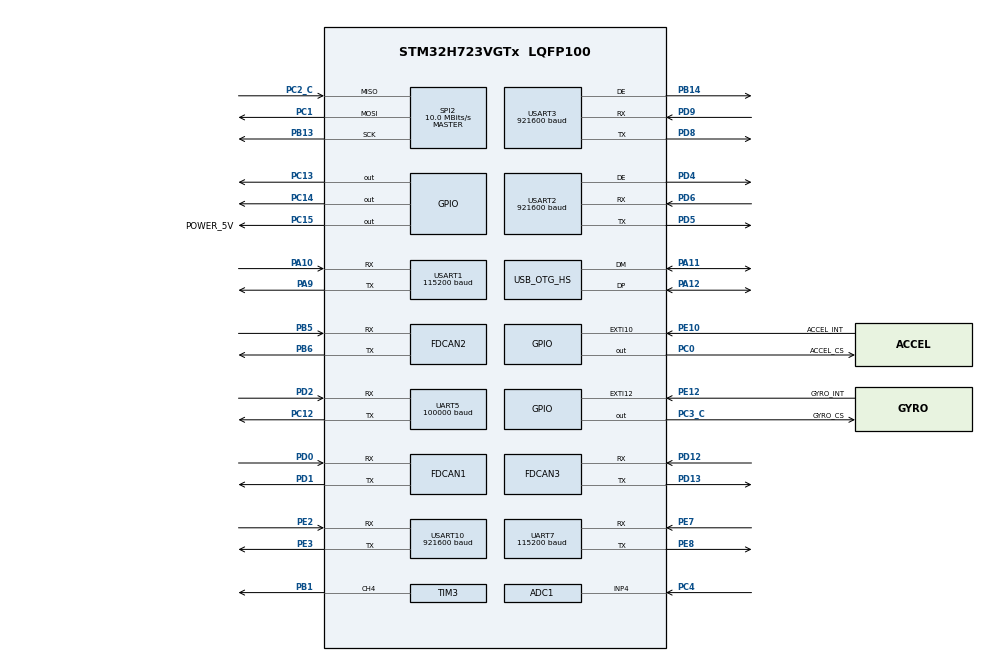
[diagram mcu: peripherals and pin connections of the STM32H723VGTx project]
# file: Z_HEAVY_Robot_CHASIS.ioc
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ADC1.Channel-2\#ChannelRegularConversion=ADC_CHANNEL_4
ADC1.Channel-3\#ChannelRegularConversion=ADC_CHANNEL_4
ADC1.ClockPrescaler=ADC_CLOCK_ASYNC_DIV64
ADC1.ClockPrescalerADC3=ADC_CLOCK_SYNC_PCLK_DIV4
ADC1.ContinuousConvMode=ENABLE
ADC1.ConversionDataManagement=ADC_CONVERSIONDATA_DMA_CIRCULAR
ADC1.NbrOfConversion=2
ADC1.NbrOfConversionFlag=1
ADC1.OffsetNumber-2\#ChannelRegularConversion=ADC_OFFSET_NONE
ADC1.OffsetNumber-3\#ChannelRegularConversion=ADC_OFFSET_NONE
ADC1.OffsetSignedSaturation-2\#ChannelRegularConversion=DISABLE
ADC1.OffsetSignedSaturation-3\#ChannelRegularConversion=DISABLE
ADC1.Rank-2\#ChannelRegularConversion=1
ADC1.Rank-3\#ChannelRegularConversion=2
ADC1.SamplingTime-2\#ChannelRegularConversion=ADC_SAMPLETIME_32CYCLES_5
ADC1.SamplingTime-3\#ChannelRegularConversion=ADC_SAMPLETIME_1CYCLE_5
ADC1.master=1
ADC3.Channel-0\#ChannelRegularConversion=ADC_CHANNEL_TEMPSENSOR
ADC3.ClockPrescalerADC3=ADC_CLOCK_SYNC_PCLK_DIV4
ADC3.DiscontinuousConvMode=ENABLE
ADC3.NbrOfConversionFlag=1
ADC3.OffsetNumber-0\#ChannelRegularConversion=ADC_OFFSET_NONE
ADC3.OffsetSign-0\#ChannelRegularConversion=ADC3_OFFSET_SIGN_NEGATIVE
ADC3.Rank-0\#ChannelRegularConversion=1
ADC3.SamplingTime-0\#ChannelRegularConversion=ADC3_SAMPLETIME_2CYCLES_5
Bdma.ADC3.0.Direction=DMA_PERIPH_TO_MEMORY
Bdma.ADC3.0.EventEnable=DISABLE
Bdma.ADC3.0.Instance=BDMA_Channel0
Bdma.ADC3.0.MemDataAlignment=DMA_MDATAALIGN_HALFWORD
Bdma.ADC3.0.MemInc=DMA_MINC_ENABLE
Bdma.ADC3.0.Mode=DMA_CIRCULAR
Bdma.ADC3.0.PeriphDataAlignment=DMA_PDATAALIGN_HALFWORD
Bdma.ADC3.0.PeriphInc=DMA_PINC_DISABLE
Bdma.ADC3.0.Polarity=HAL_DMAMUX_REQ_GEN_RISING
Bdma.ADC3.0.Priority=DMA_PRIORITY_LOW
Bdma.ADC3.0.RequestNumber=1
Bdma.ADC3.0.SignalID=NONE
Bdma.ADC3.0.SyncEnable=DISABLE
Bdma.ADC3.0.SyncPolarity=HAL_DMAMUX_SYNC_NO_EVENT
Bdma.ADC3.0.SyncRequestNumber=1
Bdma.ADC3.0.SyncSignalID=NONE
Bdma.Request0=ADC3
Bdma.RequestsNb=1
CORTEX_M7.AccessPermission-Cortex_Memory_Protection_Unit_Region0_Settings=MPU_REGION_FULL_ACCESS
CORTEX_M7.AccessPermission_Spec=MPU_REGION_FULL_ACCESS
CORTEX_M7.BaseAddress-Cortex_Memory_Protection_Unit_Region0_Settings=0x24000000
CORTEX_M7.BaseAddress_Spec=0x24000000
CORTEX_M7.CPU_DCache=Enabled
CORTEX_M7.CPU_ICache=Enabled
CORTEX_M7.DisableExec_Spec=MPU_INSTRUCTION_ACCESS_ENABLE
CORTEX_M7.Enable-Cortex_Memory_Protection_Unit_Region0_Settings=MPU_REGION_ENABLE
CORTEX_M7.IsBufferable_Spec=MPU_ACCESS_NOT_BUFFERABLE
CORTEX_M7.IsCacheable_Spec=MPU_ACCESS_NOT_CACHEABLE
CORTEX_M7.IsShareable_Spec=MPU_ACCESS_NOT_SHAREABLE
CORTEX_M7.MPU_Control=MPU_HFNMI_PRIVDEF
CORTEX_M7.Size-Cortex_Memory_Protection_Unit_Region0_Settings=MPU_REGION_SIZE_512KB
CORTEX_M7.Size_Spec=MPU_REGION_SIZE_512KB
CORTEX_M7.SubRegionDisable_Spec=0x0
CORTEX_M7.TypeExtField-Cortex_Memory_Protection_Unit_Region0_Settings=MPU_TEX_LEVEL1
CORTEX_M7.TypeExtField_Spec=MPU_TEX_LEVEL1
CORTEX_M7.default_mode_Activation=1
Dma.ADC1.14.Direction=DMA_PERIPH_TO_MEMORY
Dma.ADC1.14.EventEnable=DISABLE
Dma.ADC1.14.FIFOMode=DMA_FIFOMODE_DISABLE
Dma.ADC1.14.Instance=DMA2_Stream6
Dma.ADC1.14.MemDataAlignment=DMA_MDATAALIGN_HALFWORD
Dma.ADC1.14.MemInc=DMA_MINC_ENABLE
Dma.ADC1.14.Mode=DMA_CIRCULAR
Dma.ADC1.14.PeriphDataAlignment=DMA_PDATAALIGN_HALFWORD
Dma.ADC1.14.PeriphInc=DMA_PINC_DISABLE
Dma.ADC1.14.Polarity=HAL_DMAMUX_REQ_GEN_RISING
Dma.ADC1.14.Priority=DMA_PRIORITY_LOW
Dma.ADC1.14.RequestNumber=1
Dma.ADC1.14.SignalID=NONE
Dma.ADC1.14.SyncEnable=DISABLE
Dma.ADC1.14.SyncPolarity=HAL_DMAMUX_SYNC_NO_EVENT
Dma.ADC1.14.SyncRequestNumber=1
Dma.ADC1.14.SyncSignalID=NONE
Dma.MEMTOMEM.11.Direction=DMA_MEMORY_TO_MEMORY
Dma.MEMTOMEM.11.EventEnable=DISABLE
Dma.MEMTOMEM.11.FIFOMode=DMA_FIFOMODE_ENABLE
Dma.MEMTOMEM.11.FIFOThreshold=DMA_FIFO_THRESHOLD_FULL
Dma.MEMTOMEM.11.Instance=DMA1_Stream0
Dma.MEMTOMEM.11.MemBurst=DMA_MBURST_SINGLE
Dma.MEMTOMEM.11.MemDataAlignment=DMA_MDATAALIGN_BYTE
Dma.MEMTOMEM.11.MemInc=DMA_MINC_ENABLE
Dma.MEMTOMEM.11.Mode=DMA_NORMAL
Dma.MEMTOMEM.11.PeriphBurst=DMA_PBURST_SINGLE
Dma.MEMTOMEM.11.PeriphDataAlignment=DMA_PDATAALIGN_BYTE
Dma.MEMTOMEM.11.PeriphInc=DMA_PINC_ENABLE
Dma.MEMTOMEM.11.Polarity=HAL_DMAMUX_REQ_GEN_RISING
Dma.MEMTOMEM.11.Priority=DMA_PRIORITY_LOW
Dma.MEMTOMEM.11.RequestNumber=1
Dma.MEMTOMEM.11.SignalID=NONE
Dma.MEMTOMEM.11.SyncEnable=DISABLE
Dma.MEMTOMEM.11.SyncPolarity=HAL_DMAMUX_SYNC_NO_EVENT
Dma.MEMTOMEM.11.SyncRequestNumber=1
Dma.MEMTOMEM.11.SyncSignalID=NONE
Dma.Request0=UART5_RX
Dma.Request1=SPI2_RX
Dma.Request10=USART3_TX
Dma.Request11=MEMTOMEM
Dma.Request12=USART10_RX
Dma.Request13=USART10_TX
Dma.Request14=ADC1
Dma.Request2=SPI2_TX
Dma.Request3=UART7_RX
Dma.Request4=UART7_TX
Dma.Request5=USART1_RX
Dma.Request6=USART1_TX
Dma.Request7=USART2_RX
Dma.Request8=USART2_TX
Dma.Request9=USART3_RX
Dma.SPI2_RX.1.Direction=DMA_PERIPH_TO_MEMORY
Dma.SPI2_RX.1.EventEnable=DISABLE
Dma.SPI2_RX.1.FIFOMode=DMA_FIFOMODE_DISABLE
Dma.SPI2_RX.1.Instance=DMA1_Stream1
Dma.SPI2_RX.1.MemDataAlignment=DMA_MDATAALIGN_BYTE
Dma.SPI2_RX.1.MemInc=DMA_MINC_ENABLE
Dma.SPI2_RX.1.Mode=DMA_NORMAL
Dma.SPI2_RX.1.PeriphDataAlignment=DMA_PDATAALIGN_BYTE
Dma.SPI2_RX.1.PeriphInc=DMA_PINC_DISABLE
Dma.SPI2_RX.1.Polarity=HAL_DMAMUX_REQ_GEN_RISING
Dma.SPI2_RX.1.Priority=DMA_PRIORITY_VERY_HIGH
Dma.SPI2_RX.1.RequestNumber=1
Dma.SPI2_RX.1.SignalID=NONE
Dma.SPI2_RX.1.SyncEnable=DISABLE
Dma.SPI2_RX.1.SyncPolarity=HAL_DMAMUX_SYNC_NO_EVENT
Dma.SPI2_RX.1.SyncRequestNumber=1
Dma.SPI2_RX.1.SyncSignalID=NONE
Dma.SPI2_TX.2.Direction=DMA_MEMORY_TO_PERIPH
Dma.SPI2_TX.2.EventEnable=DISABLE
Dma.SPI2_TX.2.FIFOMode=DMA_FIFOMODE_DISABLE
Dma.SPI2_TX.2.Instance=DMA1_Stream2
Dma.SPI2_TX.2.MemDataAlignment=DMA_MDATAALIGN_BYTE
Dma.SPI2_TX.2.MemInc=DMA_MINC_ENABLE
Dma.SPI2_TX.2.Mode=DMA_NORMAL
Dma.SPI2_TX.2.PeriphDataAlignment=DMA_PDATAALIGN_BYTE
Dma.SPI2_TX.2.PeriphInc=DMA_PINC_DISABLE
Dma.SPI2_TX.2.Polarity=HAL_DMAMUX_REQ_GEN_RISING
Dma.SPI2_TX.2.Priority=DMA_PRIORITY_MEDIUM
Dma.SPI2_TX.2.RequestNumber=1
Dma.SPI2_TX.2.SignalID=NONE
Dma.SPI2_TX.2.SyncEnable=DISABLE
Dma.SPI2_TX.2.SyncPolarity=HAL_DMAMUX_SYNC_NO_EVENT
Dma.SPI2_TX.2.SyncRequestNumber=1
Dma.SPI2_TX.2.SyncSignalID=NONE
Dma.UART5_RX.0.Direction=DMA_PERIPH_TO_MEMORY
Dma.UART5_RX.0.EventEnable=DISABLE
Dma.UART5_RX.0.FIFOMode=DMA_FIFOMODE_DISABLE
Dma.UART5_RX.0.Instance=DMA2_Stream3
Dma.UART5_RX.0.MemDataAlignment=DMA_MDATAALIGN_BYTE
Dma.UART5_RX.0.MemInc=DMA_MINC_ENABLE
Dma.UART5_RX.0.Mode=DMA_CIRCULAR
Dma.UART5_RX.0.PeriphDataAlignment=DMA_PDATAALIGN_BYTE
Dma.UART5_RX.0.PeriphInc=DMA_PINC_DISABLE
Dma.UART5_RX.0.Polarity=HAL_DMAMUX_REQ_GEN_RISING
Dma.UART5_RX.0.Priority=DMA_PRIORITY_VERY_HIGH
Dma.UART5_RX.0.RequestNumber=1
Dma.UART5_RX.0.SignalID=NONE
Dma.UART5_RX.0.SyncEnable=DISABLE
Dma.UART5_RX.0.SyncPolarity=HAL_DMAMUX_SYNC_NO_EVENT
Dma.UART5_RX.0.SyncRequestNumber=1
Dma.UART5_RX.0.SyncSignalID=NONE
Dma.UART7_RX.3.Direction=DMA_PERIPH_TO_MEMORY
Dma.UART7_RX.3.EventEnable=DISABLE
Dma.UART7_RX.3.FIFOMode=DMA_FIFOMODE_DISABLE
Dma.UART7_RX.3.Instance=DMA1_Stream3
Dma.UART7_RX.3.MemDataAlignment=DMA_MDATAALIGN_BYTE
Dma.UART7_RX.3.MemInc=DMA_MINC_ENABLE
Dma.UART7_RX.3.Mode=DMA_CIRCULAR
Dma.UART7_RX.3.PeriphDataAlignment=DMA_PDATAALIGN_BYTE
Dma.UART7_RX.3.PeriphInc=DMA_PINC_DISABLE
Dma.UART7_RX.3.Polarity=HAL_DMAMUX_REQ_GEN_RISING
Dma.UART7_RX.3.Priority=DMA_PRIORITY_LOW
Dma.UART7_RX.3.RequestNumber=1
Dma.UART7_RX.3.SignalID=NONE
Dma.UART7_RX.3.SyncEnable=DISABLE
Dma.UART7_RX.3.SyncPolarity=HAL_DMAMUX_SYNC_NO_EVENT
Dma.UART7_RX.3.SyncRequestNumber=1
Dma.UART7_RX.3.SyncSignalID=NONE
Dma.UART7_TX.4.Direction=DMA_MEMORY_TO_PERIPH
Dma.UART7_TX.4.EventEnable=DISABLE
Dma.UART7_TX.4.FIFOMode=DMA_FIFOMODE_DISABLE
Dma.UART7_TX.4.Instance=DMA1_Stream4
Dma.UART7_TX.4.MemDataAlignment=DMA_MDATAALIGN_BYTE
Dma.UART7_TX.4.MemInc=DMA_MINC_ENABLE
Dma.UART7_TX.4.Mode=DMA_NORMAL
Dma.UART7_TX.4.PeriphDataAlignment=DMA_PDATAALIGN_BYTE
Dma.UART7_TX.4.PeriphInc=DMA_PINC_DISABLE
Dma.UART7_TX.4.Polarity=HAL_DMAMUX_REQ_GEN_RISING
Dma.UART7_TX.4.Priority=DMA_PRIORITY_LOW
Dma.UART7_TX.4.RequestNumber=1
Dma.UART7_TX.4.SignalID=NONE
Dma.UART7_TX.4.SyncEnable=DISABLE
Dma.UART7_TX.4.SyncPolarity=HAL_DMAMUX_SYNC_NO_EVENT
Dma.UART7_TX.4.SyncRequestNumber=1
Dma.UART7_TX.4.SyncSignalID=NONE
Dma.USART10_RX.12.Direction=DMA_PERIPH_TO_MEMORY
Dma.USART10_RX.12.EventEnable=DISABLE
Dma.USART10_RX.12.FIFOMode=DMA_FIFOMODE_DISABLE
Dma.USART10_RX.12.Instance=DMA2_Stream4
Dma.USART10_RX.12.MemDataAlignment=DMA_MDATAALIGN_BYTE
Dma.USART10_RX.12.MemInc=DMA_MINC_ENABLE
Dma.USART10_RX.12.Mode=DMA_CIRCULAR
Dma.USART10_RX.12.PeriphDataAlignment=DMA_PDATAALIGN_BYTE
Dma.USART10_RX.12.PeriphInc=DMA_PINC_DISABLE
Dma.USART10_RX.12.Polarity=HAL_DMAMUX_REQ_GEN_RISING
Dma.USART10_RX.12.Priority=DMA_PRIORITY_VERY_HIGH
Dma.USART10_RX.12.RequestNumber=1
Dma.USART10_RX.12.SignalID=NONE
Dma.USART10_RX.12.SyncEnable=DISABLE
Dma.USART10_RX.12.SyncPolarity=HAL_DMAMUX_SYNC_NO_EVENT
Dma.USART10_RX.12.SyncRequestNumber=1
Dma.USART10_RX.12.SyncSignalID=NONE
Dma.USART10_TX.13.Direction=DMA_MEMORY_TO_PERIPH
Dma.USART10_TX.13.EventEnable=DISABLE
Dma.USART10_TX.13.FIFOMode=DMA_FIFOMODE_DISABLE
Dma.USART10_TX.13.Instance=DMA2_Stream5
Dma.USART10_TX.13.MemDataAlignment=DMA_MDATAALIGN_BYTE
Dma.USART10_TX.13.MemInc=DMA_MINC_ENABLE
Dma.USART10_TX.13.Mode=DMA_NORMAL
Dma.USART10_TX.13.PeriphDataAlignment=DMA_PDATAALIGN_BYTE
Dma.USART10_TX.13.PeriphInc=DMA_PINC_DISABLE
Dma.USART10_TX.13.Polarity=HAL_DMAMUX_REQ_GEN_RISING
Dma.USART10_TX.13.Priority=DMA_PRIORITY_VERY_HIGH
Dma.USART10_TX.13.RequestNumber=1
Dma.USART10_TX.13.SignalID=NONE
Dma.USART10_TX.13.SyncEnable=DISABLE
Dma.USART10_TX.13.SyncPolarity=HAL_DMAMUX_SYNC_NO_EVENT
Dma.USART10_TX.13.SyncRequestNumber=1
Dma.USART10_TX.13.SyncSignalID=NONE
Dma.USART1_RX.5.Direction=DMA_PERIPH_TO_MEMORY
Dma.USART1_RX.5.EventEnable=DISABLE
Dma.USART1_RX.5.FIFOMode=DMA_FIFOMODE_DISABLE
Dma.USART1_RX.5.Instance=DMA1_Stream5
Dma.USART1_RX.5.MemDataAlignment=DMA_MDATAALIGN_BYTE
Dma.USART1_RX.5.MemInc=DMA_MINC_ENABLE
Dma.USART1_RX.5.Mode=DMA_NORMAL
Dma.USART1_RX.5.PeriphDataAlignment=DMA_PDATAALIGN_BYTE
Dma.USART1_RX.5.PeriphInc=DMA_PINC_DISABLE
Dma.USART1_RX.5.Polarity=HAL_DMAMUX_REQ_GEN_RISING
Dma.USART1_RX.5.Priority=DMA_PRIORITY_VERY_HIGH
Dma.USART1_RX.5.RequestNumber=1
Dma.USART1_RX.5.SignalID=NONE
Dma.USART1_RX.5.SyncEnable=DISABLE
Dma.USART1_RX.5.SyncPolarity=HAL_DMAMUX_SYNC_NO_EVENT
Dma.USART1_RX.5.SyncRequestNumber=1
Dma.USART1_RX.5.SyncSignalID=NONE
Dma.USART1_TX.6.Direction=DMA_MEMORY_TO_PERIPH
Dma.USART1_TX.6.EventEnable=DISABLE
Dma.USART1_TX.6.FIFOMode=DMA_FIFOMODE_DISABLE
Dma.USART1_TX.6.Instance=DMA1_Stream6
Dma.USART1_TX.6.MemDataAlignment=DMA_MDATAALIGN_BYTE
Dma.USART1_TX.6.MemInc=DMA_MINC_ENABLE
Dma.USART1_TX.6.Mode=DMA_NORMAL
Dma.USART1_TX.6.PeriphDataAlignment=DMA_PDATAALIGN_BYTE
Dma.USART1_TX.6.PeriphInc=DMA_PINC_DISABLE
Dma.USART1_TX.6.Polarity=HAL_DMAMUX_REQ_GEN_RISING
Dma.USART1_TX.6.Priority=DMA_PRIORITY_VERY_HIGH
Dma.USART1_TX.6.RequestNumber=1
Dma.USART1_TX.6.SignalID=NONE
Dma.USART1_TX.6.SyncEnable=DISABLE
Dma.USART1_TX.6.SyncPolarity=HAL_DMAMUX_SYNC_NO_EVENT
Dma.USART1_TX.6.SyncRequestNumber=1
Dma.USART1_TX.6.SyncSignalID=NONE
Dma.USART2_RX.7.Direction=DMA_PERIPH_TO_MEMORY
Dma.USART2_RX.7.EventEnable=DISABLE
Dma.USART2_RX.7.FIFOMode=DMA_FIFOMODE_DISABLE
Dma.USART2_RX.7.Instance=DMA1_Stream7
Dma.USART2_RX.7.MemDataAlignment=DMA_MDATAALIGN_BYTE
Dma.USART2_RX.7.MemInc=DMA_MINC_ENABLE
Dma.USART2_RX.7.Mode=DMA_CIRCULAR
Dma.USART2_RX.7.PeriphDataAlignment=DMA_PDATAALIGN_BYTE
Dma.USART2_RX.7.PeriphInc=DMA_PINC_DISABLE
Dma.USART2_RX.7.Polarity=HAL_DMAMUX_REQ_GEN_RISING
Dma.USART2_RX.7.Priority=DMA_PRIORITY_MEDIUM
Dma.USART2_RX.7.RequestNumber=1
Dma.USART2_RX.7.SignalID=NONE
Dma.USART2_RX.7.SyncEnable=DISABLE
Dma.USART2_RX.7.SyncPolarity=HAL_DMAMUX_SYNC_NO_EVENT
Dma.USART2_RX.7.SyncRequestNumber=1
Dma.USART2_RX.7.SyncSignalID=NONE
Dma.USART2_TX.8.Direction=DMA_MEMORY_TO_PERIPH
Dma.USART2_TX.8.EventEnable=DISABLE
Dma.USART2_TX.8.FIFOMode=DMA_FIFOMODE_DISABLE
Dma.USART2_TX.8.Instance=DMA2_Stream0
Dma.USART2_TX.8.MemDataAlignment=DMA_MDATAALIGN_BYTE
Dma.USART2_TX.8.MemInc=DMA_MINC_ENABLE
Dma.USART2_TX.8.Mode=DMA_NORMAL
Dma.USART2_TX.8.PeriphDataAlignment=DMA_PDATAALIGN_BYTE
Dma.USART2_TX.8.PeriphInc=DMA_PINC_DISABLE
Dma.USART2_TX.8.Polarity=HAL_DMAMUX_REQ_GEN_RISING
Dma.USART2_TX.8.Priority=DMA_PRIORITY_MEDIUM
Dma.USART2_TX.8.RequestNumber=1
Dma.USART2_TX.8.SignalID=NONE
Dma.USART2_TX.8.SyncEnable=DISABLE
Dma.USART2_TX.8.SyncPolarity=HAL_DMAMUX_SYNC_NO_EVENT
Dma.USART2_TX.8.SyncRequestNumber=1
Dma.USART2_TX.8.SyncSignalID=NONE
Dma.USART3_RX.9.Direction=DMA_PERIPH_TO_MEMORY
Dma.USART3_RX.9.EventEnable=DISABLE
Dma.USART3_RX.9.FIFOMode=DMA_FIFOMODE_DISABLE
Dma.USART3_RX.9.Instance=DMA2_Stream1
Dma.USART3_RX.9.MemDataAlignment=DMA_MDATAALIGN_BYTE
Dma.USART3_RX.9.MemInc=DMA_MINC_ENABLE
Dma.USART3_RX.9.Mode=DMA_CIRCULAR
Dma.USART3_RX.9.PeriphDataAlignment=DMA_PDATAALIGN_BYTE
Dma.USART3_RX.9.PeriphInc=DMA_PINC_DISABLE
Dma.USART3_RX.9.Polarity=HAL_DMAMUX_REQ_GEN_RISING
Dma.USART3_RX.9.Priority=DMA_PRIORITY_MEDIUM
Dma.USART3_RX.9.RequestNumber=1
Dma.USART3_RX.9.SignalID=NONE
Dma.USART3_RX.9.SyncEnable=DISABLE
Dma.USART3_RX.9.SyncPolarity=HAL_DMAMUX_SYNC_NO_EVENT
Dma.USART3_RX.9.SyncRequestNumber=1
Dma.USART3_RX.9.SyncSignalID=NONE
Dma.USART3_TX.10.Direction=DMA_MEMORY_TO_PERIPH
Dma.USART3_TX.10.EventEnable=DISABLE
Dma.USART3_TX.10.FIFOMode=DMA_FIFOMODE_DISABLE
Dma.USART3_TX.10.Instance=DMA2_Stream2
Dma.USART3_TX.10.MemDataAlignment=DMA_MDATAALIGN_BYTE
Dma.USART3_TX.10.MemInc=DMA_MINC_ENABLE
Dma.USART3_TX.10.Mode=DMA_NORMAL
Dma.USART3_TX.10.PeriphDataAlignment=DMA_PDATAALIGN_BYTE
Dma.USART3_TX.10.PeriphInc=DMA_PINC_DISABLE
Dma.USART3_TX.10.Polarity=HAL_DMAMUX_REQ_GEN_RISING
Dma.USART3_TX.10.Priority=DMA_PRIORITY_MEDIUM
Dma.USART3_TX.10.RequestNumber=1
Dma.USART3_TX.10.SignalID=NONE
Dma.USART3_TX.10.SyncEnable=DISABLE
Dma.USART3_TX.10.SyncPolarity=HAL_DMAMUX_SYNC_NO_EVENT
Dma.USART3_TX.10.SyncRequestNumber=1
Dma.USART3_TX.10.SyncSignalID=NONE
FDCAN1.AutoRetransmission=DISABLE
FDCAN1.CalculateBaudRateNominal=1000000
FDCAN1.CalculateTimeBitNominal=1000
FDCAN1.CalculateTimeQuantumNominal=50.0
FDCAN1.ClockCalibrationCCU=DISABLE
FDCAN1.DataPrescaler=5
FDCAN1.DataSyncJumpWidth=5
FDCAN1.DataTimeSeg1=14
FDCAN1.DataTimeSeg2=5
FDCAN1.ExtFiltersNbr=0
FDCAN1.FrameFormat=FDCAN_FRAME_CLASSIC
FDCAN1.NominalPrescaler=5
FDCAN1.NominalSyncJumpWidth=5
FDCAN1.NominalTimeSeg1=14
FDCAN1.NominalTimeSeg2=5
FDCAN1.ProtocolException=ENABLE
FDCAN1.RxBufferSize=FDCAN_DATA_BYTES_8
FDCAN1.RxFifo0ElmtSize=FDCAN_DATA_BYTES_8
FDCAN1.RxFifo0ElmtsNbr=8
FDCAN1.RxFifo1ElmtSize=FDCAN_DATA_BYTES_8
FDCAN1.StdFiltersNbr=1
FDCAN1.TransmitPause=DISABLE
FDCAN1.TxElmtSize=FDCAN_DATA_BYTES_8
FDCAN1.TxFifoQueueElmtsNbr=8
FDCAN1.TxFifoQueueMode=FDCAN_TX_FIFO_OPERATION
FDCAN2.CalculateBaudRateNominal=1000000
FDCAN2.CalculateTimeBitNominal=1000
FDCAN2.CalculateTimeQuantumNominal=50.0
FDCAN2.DataPrescaler=1
FDCAN2.DataSyncJumpWidth=5
FDCAN2.DataTimeSeg1=14
FDCAN2.DataTimeSeg2=5
FDCAN2.FrameFormat=FDCAN_FRAME_CLASSIC
FDCAN2.MessageRAMOffset=853
FDCAN2.NominalPrescaler=5
FDCAN2.NominalSyncJumpWidth=5
FDCAN2.NominalTimeSeg1=14
FDCAN2.NominalTimeSeg2=5
FDCAN2.ProtocolException=ENABLE
FDCAN2.RxFifo0ElmtsNbr=0
FDCAN2.RxFifo1ElmtsNbr=8
FDCAN2.StdFiltersNbr=1
FDCAN2.TxFifoQueueElmtsNbr=8
FDCAN3.CalculateBaudRateNominal=1000000
FDCAN3.CalculateTimeBitNominal=1000
FDCAN3.CalculateTimeQuantumNominal=50.0
FDCAN3.DataPrescaler=5
FDCAN3.DataSyncJumpWidth=5
FDCAN3.DataTimeSeg1=14
FDCAN3.DataTimeSeg2=5
FDCAN3.FrameFormat=FDCAN_FRAME_CLASSIC
FDCAN3.MessageRAMOffset=1706
FDCAN3.NominalPrescaler=5
FDCAN3.NominalSyncJumpWidth=5
FDCAN3.NominalTimeSeg1=14
FDCAN3.NominalTimeSeg2=5
FDCAN3.ProtocolException=ENABLE
FDCAN3.RxFifo0ElmtsNbr=8
FDCAN3.StdFiltersNbr=1
FDCAN3.TxFifoQueueElmtsNbr=8
FREERTOS.INCLUDE_vTaskDelayUntil=1
FREERTOS.Tasks01=Start_INS_Task,2,2048,INS_Task,As weak,NULL,Static,Start_INS_TaskBuffer,Start_INS_TaskControlBlock;Start_Control_Task,1,2048,Control_Task,As weak,NULL,Static,Start_Control_TaskBuffer,Start_Control_TaskControlBlock;Start_CAN_Task,0,2048,CAN_Task,As weak,NULL,Static,Start_CAN_TaskBuffer,Start_CAN_TaskControlBlock;Start_Detect_Task,-1,2048,Detect_Task,As weak,NULL,Static,Start_Detect_TaskBuffer,Start_Detect_TaskControlBlock
FREERTOS.configMAX_TASK_NAME_LEN=64
FREERTOS.configMINIMAL_STACK_SIZE=2048
FREERTOS.configQUEUE_REGISTRY_SIZE=8
FREERTOS.configUSE_TRACE_FACILITY=1
Mcu.Family=STM32H7
Mcu.Name=STM32H723VGTx
Mcu.Package=LQFP100
NVIC.BDMA_Channel0_IRQn=true\:5\:0\:false\:false\:true\:true\:false\:true\:true
NVIC.DMA1_Stream0_IRQn=true\:5\:0\:false\:false\:true\:true\:false\:true\:true
NVIC.DMA1_Stream1_IRQn=true\:5\:0\:false\:false\:true\:true\:false\:true\:true
NVIC.DMA1_Stream2_IRQn=true\:5\:0\:false\:false\:true\:true\:false\:true\:true
NVIC.DMA1_Stream3_IRQn=true\:5\:0\:false\:false\:true\:true\:false\:true\:true
NVIC.DMA1_Stream4_IRQn=true\:5\:0\:false\:false\:true\:true\:false\:true\:true
NVIC.DMA1_Stream5_IRQn=true\:5\:0\:false\:false\:true\:true\:false\:true\:true
NVIC.DMA1_Stream6_IRQn=true\:5\:0\:false\:false\:true\:true\:false\:true\:true
NVIC.DMA1_Stream7_IRQn=true\:5\:0\:false\:false\:true\:true\:false\:true\:true
NVIC.DMA2_Stream0_IRQn=true\:5\:0\:false\:false\:true\:true\:false\:true\:true
NVIC.DMA2_Stream1_IRQn=true\:5\:0\:false\:false\:true\:true\:false\:true\:true
NVIC.DMA2_Stream2_IRQn=true\:5\:0\:false\:false\:true\:true\:false\:true\:true
NVIC.DMA2_Stream3_IRQn=true\:5\:0\:false\:false\:true\:true\:false\:true\:true
NVIC.DMA2_Stream4_IRQn=true\:5\:0\:false\:false\:true\:true\:false\:true\:true
NVIC.DMA2_Stream5_IRQn=true\:5\:0\:false\:false\:true\:true\:false\:true\:true
NVIC.DMA2_Stream6_IRQn=true\:5\:0\:false\:false\:true\:true\:false\:true\:true
NVIC.FDCAN1_IT0_IRQn=true\:5\:0\:false\:false\:true\:true\:true\:true\:true
NVIC.FDCAN1_IT1_IRQn=true\:5\:0\:false\:false\:true\:true\:true\:true\:true
NVIC.FDCAN2_IT0_IRQn=true\:5\:0\:false\:false\:true\:true\:true\:true\:true
NVIC.FDCAN2_IT1_IRQn=true\:5\:0\:false\:false\:true\:true\:true\:true\:true
NVIC.FDCAN3_IT0_IRQn=true\:5\:0\:false\:false\:true\:true\:true\:true\:true
NVIC.FDCAN3_IT1_IRQn=true\:5\:0\:false\:false\:true\:true\:true\:true\:true
NVIC.OTG_HS_IRQn=true\:5\:0\:false\:false\:true\:true\:true\:true\:true
NVIC.PriorityGroup=NVIC_PRIORITYGROUP_4
NVIC.SPI2_IRQn=true\:5\:0\:true\:false\:true\:true\:false\:true\:true
NVIC.TIM2_IRQn=true\:15\:0\:false\:false\:true\:false\:false\:true\:true
NVIC.TimeBase=TIM2_IRQn
NVIC.TimeBaseIP=TIM2
NVIC.UART5_IRQn=true\:5\:0\:false\:false\:true\:true\:true\:true\:true
NVIC.UART7_IRQn=true\:5\:0\:false\:false\:true\:true\:true\:true\:true
NVIC.USART10_IRQn=true\:5\:0\:false\:false\:true\:true\:true\:true\:true
NVIC.USART1_IRQn=true\:5\:0\:false\:false\:true\:true\:true\:true\:true
NVIC.USART2_IRQn=true\:5\:0\:false\:false\:true\:true\:true\:true\:true
NVIC.USART3_IRQn=true\:5\:0\:false\:false\:true\:true\:true\:true\:true
PA10.Mode=Asynchronous
PA10.Signal=USART1_RX
PA11.Mode=Device_Only_FS
PA11.Signal=USB_OTG_HS_DM
PA12.Mode=Device_Only_FS
PA12.Signal=USB_OTG_HS_DP
PA13(JTMS/SWDIO).Mode=Serial_Wire
PA13(JTMS/SWDIO).Signal=DEBUG_JTMS-SWDIO
PA14(JTCK/SWCLK).Mode=Serial_Wire
PA14(JTCK/SWCLK).Signal=DEBUG_JTCK-SWCLK
PA9.Mode=Asynchronous
PA9.Signal=USART1_TX
PB1.Signal=S_TIM3_CH4
PB13.GPIO_Speed=GPIO_SPEED_FREQ_VERY_HIGH
PB13.Mode=Full_Duplex_Master
PB13.Signal=SPI2_SCK
PB14.Mode=Hardware Flow Control (RS485)
PB14.Signal=USART3_DE
PB5.Mode=FDCAN_Activate
PB5.Signal=FDCAN2_RX
PB6.GPIO_FM6=__NULL
PB6.Mode=FDCAN_Activate
PB6.Signal=FDCAN2_TX
PC0.GPIO_Label=ACCEL_CS
PC0.GPIO_PuPd=GPIO_NOPULL
PC0.GPIO_Speed=GPIO_SPEED_FREQ_MEDIUM
PC0.PinState=GPIO_PIN_SET
PC0.Signal=GPIO_Output
PC1.GPIO_Speed=GPIO_SPEED_FREQ_VERY_HIGH
PC1.Mode=Full_Duplex_Master
PC1.Signal=SPI2_MOSI
PC12.Mode=Asynchronous
PC12.Signal=UART5_TX
PC13.PinState=GPIO_PIN_RESET
PC13.Signal=GPIO_Output
PC14-OSC32_IN.Signal=GPIO_Output
PC15-OSC32_OUT.GPIO_Label=POWER_5V
PC15-OSC32_OUT.PinState=GPIO_PIN_SET
PC15-OSC32_OUT.Signal=GPIO_Output
PC2_C.GPIO_Speed=GPIO_SPEED_FREQ_VERY_HIGH
PC2_C.Mode=Full_Duplex_Master
PC2_C.Signal=SPI2_MISO
PC3_C.GPIO_Label=GYRO_CS
PC3_C.GPIO_PuPd=GPIO_NOPULL
PC3_C.GPIO_Speed=GPIO_SPEED_FREQ_MEDIUM
PC3_C.PinState=GPIO_PIN_SET
PC3_C.Signal=GPIO_Output
PC4.Signal=ADCx_INP4
PD0.Mode=FDCAN_Activate
PD0.Signal=FDCAN1_RX
PD1.Mode=FDCAN_Activate
PD1.Signal=FDCAN1_TX
PD12.Mode=FDCAN_Activate
PD12.Signal=FDCAN3_RX
PD13.Mode=FDCAN_Activate
PD13.Signal=FDCAN3_TX
PD2.GPIO_Speed=GPIO_SPEED_FREQ_VERY_HIGH
PD2.Mode=Asynchronous
PD2.Signal=UART5_RX
PD4.Mode=Hardware Flow Control (RS485)
PD4.Signal=USART2_DE
PD5.Mode=Asynchronous
PD5.Signal=USART2_TX
PD6.Mode=Asynchronous
PD6.Signal=USART2_RX
PD8.Mode=Asynchronous
PD8.Signal=USART3_TX
PD9.Mode=Asynchronous
PD9.Signal=USART3_RX
PE10.GPIO_Label=ACCEL_INT
PE10.GPIO_PuPd=GPIO_NOPULL
PE10.Signal=GPXTI10
PE12.GPIO_Label=GYRO_INT
PE12.GPIO_PuPd=GPIO_NOPULL
PE12.Signal=GPXTI12
PE2.Mode=Asynchronous
PE2.Signal=USART10_RX
PE3.Mode=Asynchronous
PE3.Signal=USART10_TX
PE7.Mode=Asynchronous
PE7.Signal=UART7_RX
PE8.Mode=Asynchronous
PE8.Signal=UART7_TX
PH0-OSC_IN.Mode=HSE-External-Oscillator
PH0-OSC_IN.Signal=RCC_OSC_IN
PH1-OSC_OUT.Mode=HSE-External-Oscillator
PH1-OSC_OUT.Signal=RCC_OSC_OUT
ProjectManager.HeapSize=0x2000
ProjectManager.StackSize=0x4000
ProjectManager.TargetToolchain=CMake
RCC.ADCCLockSelection=RCC_ADCCLKSOURCE_CLKP
RCC.ADCFreq_Value=64000000
RCC.APB1Freq_Value=80000000
RCC.APB2Freq_Value=80000000
RCC.APB3Freq_Value=80000000
RCC.APB4Freq_Value=80000000
RCC.CortexFreq_Value=640000000
RCC.D1PPRE=RCC_APB3_DIV2
RCC.D2PPRE1=RCC_APB1_DIV2
RCC.D2PPRE2=RCC_APB2_DIV2
RCC.D3PPRE=RCC_APB4_DIV2
RCC.DIVM1=6
RCC.DIVM2=24
RCC.DIVM3=24
RCC.DIVN1=160
RCC.DIVN2=200
RCC.DIVN3=160
RCC.DIVP1=1
RCC.DIVQ1=4
RCC.EnbaleCSS=false
RCC.FDCANCLockSelection=RCC_FDCANCLKSOURCE_PLL2
RCC.FLatency-AdvancedSettings=FLASH_LATENCY_2
RCC.HCLKFreq_Value=160000000
RCC.HPRE=RCC_HCLK_DIV4
RCC.HSE_VALUE=24000000
RCC.PLL1_VCI_Range-AdvancedSettings=RCC_PLL1VCIRANGE_0
RCC.PLL1_VCO_SEL-AdvancedSettings=RCC_PLL1VCOMEDIUM
RCC.PLL2FRACN=0
RCC.PLL2_VCO_SEL-AdvancedSettings=RCC_PLL2VCOWIDE
RCC.PLL3FRACN=0
RCC.PLL3_VCO_SEL-AdvancedSettings=RCC_PLL3VCOWIDE
RCC.PLLFRACN=0
RCC.PLLSourceVirtual=RCC_PLLSOURCE_HSE
RCC.SPI123CLockSelection=RCC_SPI123CLKSOURCE_PLL3
RCC.SYSCLKFreq_VALUE=640000000
RCC.SYSCLKSource=RCC_SYSCLKSOURCE_PLLCLK
RCC.USART16CLockSelection=RCC_USART16910CLKSOURCE_PLL2
RCC.USBCLockSelection=RCC_USBCLKSOURCE_HSI48
RCC.USBFreq_Value=48000000
SH.ADCx_INP4.0=ADC1_INP4,IN4-Single-Ended
SH.S_TIM3_CH4.0=TIM3_CH4,PWM Generation4 CH4
SPI2.BaudRatePrescaler=SPI_BAUDRATEPRESCALER_8
SPI2.CLKPhase=SPI_PHASE_2EDGE
SPI2.CLKPolarity=SPI_POLARITY_HIGH
SPI2.CalculateBaudRate=10.0 MBits/s
SPI2.DataSize=SPI_DATASIZE_8BIT
SPI2.Direction=SPI_DIRECTION_2LINES
SPI2.Mode=SPI_MODE_MASTER
SPI2.NSSPMode=SPI_NSS_PULSE_DISABLE
SPI2.VirtualType=VM_MASTER
TIM3.AutoReloadPreload=TIM_AUTORELOAD_PRELOAD_ENABLE
TIM3.Channel-PWM\ Generation4\ CH4=TIM_CHANNEL_4
TIM3.Period=20000
TIM3.Prescaler=80-1
UART5.BaudRate=100000
UART5.Parity=PARITY_EVEN
UART5.StopBits=UART_STOPBITS_2
UART5.WordLength=WORDLENGTH_9B
UART7.BaudRate=115200
USART1.BaudRate=115200
USART1.VirtualMode-Asynchronous=VM_ASYNC
USART10.BaudRate=921600
USART10.VirtualMode=VM_ASYNC
USART2.BaudRate=921600
USART2.OverSampling=UART_OVERSAMPLING_8
USART2.VirtualMode-Asynchronous=VM_ASYNC
USART2.VirtualMode-Hardware\ Flow\ Control\ (RS485)=VM_ASYNC
USART3.BaudRate=921600
USART3.OverSampling=UART_OVERSAMPLING_8
USART3.VirtualMode-Asynchronous=VM_ASYNC
USART3.VirtualMode-Hardware\ Flow\ Control\ (RS485)=VM_ASYNC
USB_DEVICE.CLASS_NAME_HS=CDC
USB_DEVICE.VirtualMode=Cdc
USB_DEVICE.VirtualModeHS=Cdc_HS
USB_OTG_HS.VirtualMode-Device_Only_FS=Device_Only_FS
VP_ADC3_TempSens_Input.Mode=IN-TempSens
VP_ADC3_Vbat_Input.Mode=IN-Vbat
VP_ADC3_Vref_Input.Mode=IN-Vrefint
VP_FREERTOS_VS_CMSIS_V1.Mode=CMSIS_V1
VP_MEMORYMAP_VS_MEMORYMAP.Mode=CurAppReg
VP_SYS_VS_tim2.Mode=TIM2
VP_USB_DEVICE_VS_USB_DEVICE_CDC_HS.Mode=CDC_HS
board=custom

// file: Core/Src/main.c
/* USER CODE BEGIN Header */
/**
  ******************************************************************************
  * @file           : main.c
  * @brief          : Main program body
  ******************************************************************************
  * @attention
  *
  * Copyright (c) 2024 STMicroelectronics.
  * All rights reserved.
  *
  * This software is licensed under terms that can be found in the LICENSE file
  * in the root directory of this software component.
  * If no LICENSE file comes with this software, it is provided AS-IS.
  *
  ******************************************************************************
  */
/* USER CODE END Header */
#include "main.h"
#include "cmsis_os.h"
#include "adc.h"
#include "bdma.h"
#include "dma.h"
#include "fdcan.h"
#include "spi.h"
#include "tim.h"
#include "usart.h"
#include "usb_device.h"
#include "gpio.h"

/* USER CODE BEGIN Includes */
#include "bsp_mcu.h"
#include "robot_config.h"

/* USER CODE END Includes */

void SystemClock_Config(void);
void PeriphCommonClock_Config(void);
static void MPU_Config(void);
void MX_FREERTOS_Init(void);

int main(void)
{

  /* MPU Configuration--------------------------------------------------------*/
  MPU_Config();

  /* Enable the CPU Cache */

  /* Enable I-Cache---------------------------------------------------------*/
  SCB_EnableICache();

  /* Enable D-Cache---------------------------------------------------------*/
  SCB_EnableDCache();

  /* MCU Configuration--------------------------------------------------------*/

  /* Reset of all peripherals, Initializes the Flash interface and the Systick. */
  HAL_Init();

  /* Configure the system clock */
  SystemClock_Config();

  /* Configure the peripherals common clocks */
  PeriphCommonClock_Config();

  /* Initialize all configured peripherals */
  MX_GPIO_Init();
  MX_DMA_Init();
  MX_BDMA_Init();
  MX_FDCAN1_Init();
  MX_FDCAN2_Init();
  MX_UART5_Init();
  MX_SPI2_Init();
  MX_TIM3_Init();
  MX_UART7_Init();
  MX_USART1_UART_Init();
  MX_USART2_UART_Init();
  MX_USART3_UART_Init();
  MX_USART10_UART_Init();
  MX_FDCAN3_Init();
  MX_ADC3_Init();
  MX_ADC1_Init();
  /* USER CODE BEGIN 2 */
  MCU_Init();
  (void)robot_init();

  /* USER CODE END 2 */

  /* Call init function for freertos objects (in cmsis_os2.c) */
  MX_FREERTOS_Init();

  /* Start scheduler */
  osKernelStart();

  /* We should never get here as control is now taken by the scheduler */

  /* Infinite loop */
  while (1)
  {

  }
}

void SystemClock_Config(void)
{
  RCC_OscInitTypeDef RCC_OscInitStruct = {0};
  RCC_ClkInitTypeDef RCC_ClkInitStruct = {0};

  /** Supply configuration update enable
  */
  HAL_PWREx_ConfigSupply(PWR_LDO_SUPPLY);

  /** Configure the main internal regulator output voltage
  */
  __HAL_PWR_VOLTAGESCALING_CONFIG(PWR_REGULATOR_VOLTAGE_SCALE1);

  while(!__HAL_PWR_GET_FLAG(PWR_FLAG_VOSRDY)) {}

  /** Initializes the RCC Oscillators according to the specified parameters
  * in the RCC_OscInitTypeDef structure.
  */
  RCC_OscInitStruct.OscillatorType = RCC_OSCILLATORTYPE_HSI48|RCC_OSCILLATORTYPE_HSI
                              |RCC_OSCILLATORTYPE_HSE;
  RCC_OscInitStruct.HSEState = RCC_HSE_ON;
  RCC_OscInitStruct.HSIState = RCC_HSI_DIV1;
  RCC_OscInitStruct.HSICalibrationValue = 64;
  RCC_OscInitStruct.HSI48State = RCC_HSI48_ON;
  RCC_OscInitStruct.PLL.PLLState = RCC_PLL_ON;
  RCC_OscInitStruct.PLL.PLLSource = RCC_PLLSOURCE_HSE;
  RCC_OscInitStruct.PLL.PLLM = 6;
  /* PLLN=80: 24MHz/6*80/2 = 160MHz SYSCLK。
   * 原配置 PLLN=160 得 320MHz，但供电为 VOS1（上限约 200MHz）且 Flash 仅 2WS，
   * 属超频欠压运行，会引发随机总线 HardFault（调试实测 100% 复现，
   * 关闭 CPU 写缓冲可掩盖）。降回 160MHz 后与 VOS1+FLASH_LATENCY_2 匹配。
   * PLLQ 由 4 改 2，保持 PLL1Q=160MHz 不变（FDCAN/USART 用 PLL2，不受影响）。 */
  RCC_OscInitStruct.PLL.PLLN = 80;
  RCC_OscInitStruct.PLL.PLLP = 1;
  RCC_OscInitStruct.PLL.PLLQ = 2;
  RCC_OscInitStruct.PLL.PLLR = 2;
  RCC_OscInitStruct.PLL.PLLRGE = RCC_PLL1VCIRANGE_2;
  RCC_OscInitStruct.PLL.PLLVCOSEL = RCC_PLL1VCOWIDE;
  RCC_OscInitStruct.PLL.PLLFRACN = 0;
  if (HAL_RCC_OscConfig(&RCC_OscInitStruct) != HAL_OK)
  {
    Error_Handler();
  }

  /** Initializes the CPU, AHB and APB buses clocks
  */
  RCC_ClkInitStruct.ClockType = RCC_CLOCKTYPE_HCLK|RCC_CLOCKTYPE_SYSCLK
                              |RCC_CLOCKTYPE_PCLK1|RCC_CLOCKTYPE_PCLK2
                              |RCC_CLOCKTYPE_D3PCLK1|RCC_CLOCKTYPE_D1PCLK1;
  RCC_ClkInitStruct.SYSCLKSource = RCC_SYSCLKSOURCE_PLLCLK;
  RCC_ClkInitStruct.SYSCLKDivider = RCC_SYSCLK_DIV1;
  RCC_ClkInitStruct.AHBCLKDivider = RCC_HCLK_DIV4;
  RCC_ClkInitStruct.APB3CLKDivider = RCC_APB3_DIV2;
  RCC_ClkInitStruct.APB1CLKDivider = RCC_APB1_DIV2;
  RCC_ClkInitStruct.APB2CLKDivider = RCC_APB2_DIV2;
  RCC_ClkInitStruct.APB4CLKDivider = RCC_APB4_DIV2;

  if (HAL_RCC_ClockConfig(&RCC_ClkInitStruct, FLASH_LATENCY_2) != HAL_OK)
  {
    Error_Handler();
  }
}

void PeriphCommonClock_Config(void)
{
  RCC_PeriphCLKInitTypeDef PeriphClkInitStruct = {0};

  /** Initializes the peripherals clock
  */
  PeriphClkInitStruct.PeriphClockSelection = RCC_PERIPHCLK_FDCAN|RCC_PERIPHCLK_USART1
                              |RCC_PERIPHCLK_USART10|RCC_PERIPHCLK_CKPER;
  PeriphClkInitStruct.PLL2.PLL2M = 24;
  PeriphClkInitStruct.PLL2.PLL2N = 200;
  PeriphClkInitStruct.PLL2.PLL2P = 2;
  PeriphClkInitStruct.PLL2.PLL2Q = 2;
  PeriphClkInitStruct.PLL2.PLL2R = 2;
  PeriphClkInitStruct.PLL2.PLL2RGE = RCC_PLL2VCIRANGE_0;
  PeriphClkInitStruct.PLL2.PLL2VCOSEL = RCC_PLL2VCOMEDIUM;
  PeriphClkInitStruct.PLL2.PLL2FRACN = 0;
  PeriphClkInitStruct.CkperClockSelection = RCC_CLKPSOURCE_HSI;
  PeriphClkInitStruct.FdcanClockSelection = RCC_FDCANCLKSOURCE_PLL2;
  PeriphClkInitStruct.Usart16ClockSelection = RCC_USART16910CLKSOURCE_PLL2;
  if (HAL_RCCEx_PeriphCLKConfig(&PeriphClkInitStruct) != HAL_OK)
  {
    Error_Handler();
  }
}

 /* MPU Configuration */

void MPU_Config(void)
{
  MPU_Region_InitTypeDef MPU_InitStruct = {0};

  /* Disables the MPU */
  HAL_MPU_Disable();

  /** Initializes and configures the Region and the memory to be protected
  */
  MPU_InitStruct.Enable = MPU_REGION_ENABLE;
  MPU_InitStruct.Number = MPU_REGION_NUMBER0;
  MPU_InitStruct.BaseAddress = 0x24000000;
  MPU_InitStruct.Size = MPU_REGION_SIZE_512KB;
  MPU_InitStruct.SubRegionDisable = 0x0;
  MPU_InitStruct.TypeExtField = MPU_TEX_LEVEL1;
  MPU_InitStruct.AccessPermission = MPU_REGION_FULL_ACCESS;
  MPU_InitStruct.DisableExec = MPU_INSTRUCTION_ACCESS_ENABLE;
  MPU_InitStruct.IsShareable = MPU_ACCESS_NOT_SHAREABLE;
  MPU_InitStruct.IsCacheable = MPU_ACCESS_NOT_CACHEABLE;
  MPU_InitStruct.IsBufferable = MPU_ACCESS_NOT_BUFFERABLE;

  HAL_MPU_ConfigRegion(&MPU_InitStruct);
  /* Enables the MPU */
  HAL_MPU_Enable(MPU_HFNMI_PRIVDEF);

}

void HAL_TIM_PeriodElapsedCallback(TIM_HandleTypeDef *htim)
{
  if (htim->Instance == TIM2)
  {
    HAL_IncTick();
  }
}

void Error_Handler(void)
{
  __disable_irq();
  while (1)
  {
  }
}

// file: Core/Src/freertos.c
/* USER CODE BEGIN Header */
/**
  ******************************************************************************
  * File Name          : freertos.c
  * Description        : Code for freertos applications
  ******************************************************************************
  * @attention
  *
  * Copyright (c) 2024 STMicroelectronics.
  * All rights reserved.
  *
  * This software is licensed under terms that can be found in the LICENSE file
  * in the root directory of this software component.
  * If no LICENSE file comes with this software, it is provided AS-IS.
  *
  ******************************************************************************
  */
/* USER CODE END Header */

#include "FreeRTOS.h"
#include "task.h"
#include "main.h"
#include "cmsis_os.h"

osThreadId Start_INS_TaskHandle;
uint32_t Start_INS_TaskBuffer[ 2048 ];
osStaticThreadDef_t Start_INS_TaskControlBlock;
osThreadId Start_Control_TaskHandle;
uint32_t Start_Control_TaskBuffer[ 2048 ];
osStaticThreadDef_t Start_Control_TaskControlBlock;
osThreadId Start_CAN_TaskHandle;
uint32_t Start_CAN_TaskBuffer[ 2048 ];
osStaticThreadDef_t Start_CAN_TaskControlBlock;
osThreadId Start_Detect_TaskHandle;
uint32_t Start_Detect_TaskBuffer[ 2048 ];
osStaticThreadDef_t Start_Detect_TaskControlBlock;

void INS_Task(void const * argument);
void Control_Task(void const * argument);
void CAN_Task(void const * argument);
void Detect_Task(void const * argument);

extern void MX_USB_DEVICE_Init(void);
void MX_FREERTOS_Init(void); /* (MISRA C 2004 rule 8.1) */

/* GetIdleTaskMemory prototype (linked to static allocation support) */
void vApplicationGetIdleTaskMemory( StaticTask_t **ppxIdleTaskTCBBuffer, StackType_t **ppxIdleTaskStackBuffer, uint32_t *pulIdleTaskStackSize );

/* USER CODE BEGIN GET_IDLE_TASK_MEMORY */
static StaticTask_t xIdleTaskTCBBuffer;
static StackType_t xIdleStack[configMINIMAL_STACK_SIZE];

void vApplicationGetIdleTaskMemory( StaticTask_t **ppxIdleTaskTCBBuffer, StackType_t **ppxIdleTaskStackBuffer, uint32_t *pulIdleTaskStackSize )
{
  *ppxIdleTaskTCBBuffer = &xIdleTaskTCBBuffer;
  *ppxIdleTaskStackBuffer = &xIdleStack[0];
  *pulIdleTaskStackSize = configMINIMAL_STACK_SIZE;
  /* place for user code */
}
/* USER CODE END GET_IDLE_TASK_MEMORY */

void MX_FREERTOS_Init(void) {

  /* Create the thread(s) */
  /* definition and creation of Start_INS_Task */
  osThreadStaticDef(Start_INS_Task, INS_Task, osPriorityHigh, 0, 2048, Start_INS_TaskBuffer, &Start_INS_TaskControlBlock);
  Start_INS_TaskHandle = osThreadCreate(osThread(Start_INS_Task), NULL);

  /* definition and creation of Start_Control_Task */
  osThreadStaticDef(Start_Control_Task, Control_Task, osPriorityAboveNormal, 0, 2048, Start_Control_TaskBuffer, &Start_Control_TaskControlBlock);
  Start_Control_TaskHandle = osThreadCreate(osThread(Start_Control_Task), NULL);

  /* definition and creation of Start_CAN_Task */
  osThreadStaticDef(Start_CAN_Task, CAN_Task, osPriorityNormal, 0, 2048, Start_CAN_TaskBuffer, &Start_CAN_TaskControlBlock);
  Start_CAN_TaskHandle = osThreadCreate(osThread(Start_CAN_Task), NULL);

  /* definition and creation of Start_Detect_Task */
  osThreadStaticDef(Start_Detect_Task, Detect_Task, osPriorityBelowNormal, 0, 2048, Start_Detect_TaskBuffer, &Start_Detect_TaskControlBlock);
  Start_Detect_TaskHandle = osThreadCreate(osThread(Start_Detect_Task), NULL);

}

__weak void INS_Task(void const * argument)
{
  /* init code for USB_DEVICE */
  MX_USB_DEVICE_Init();
  for(;;)
  {
    osDelay(1);
  }
}

__weak void Control_Task(void const * argument)
{
  for(;;)
  {
    osDelay(1);
  }
}

__weak void CAN_Task(void const * argument)
{
  for(;;)
  {
    osDelay(1);
  }
}

__weak void Detect_Task(void const * argument)
{
  for(;;)
  {
    osDelay(1);
  }
}
